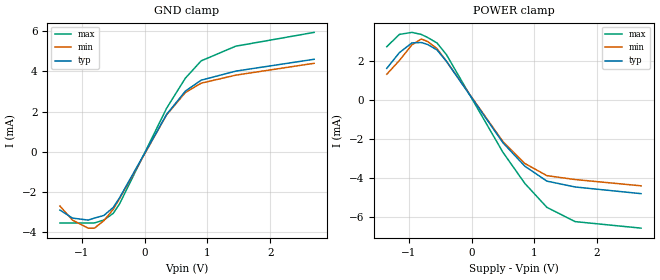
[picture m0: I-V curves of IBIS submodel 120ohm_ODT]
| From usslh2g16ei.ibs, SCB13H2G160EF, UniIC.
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| SUBMODEL 120ohm_ODT
[Submodel]   120ohm_ODT
Submodel_type  Dynamic_clamp
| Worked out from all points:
|   GND clamp passes 1 mA (typ) near -0.17 V on its own axis
|   POWER clamp passes 1 mA (typ) near -0.20 V on its own axis
[GND Clamp]
|Voltage   I(typ)   I(min)   I(max)
-1.35V    -2.9mA     -2.7mA     -3.542mA
-1.15V    -3.3mA     -3.4mA     -3.542mA
-900mV    -3.4mA     -3.8mA     -3.542mA
-800mV    -3.3mA     -3.8mA     -3.542mA
-650mV    -3.17mA    -3.43mA    -3.396mA
-500mV    -2.77mA    -2.86mA    -3.063mA
-400mV    -2.29mA    -2.33mA    -2.594mA
350mV     1.86mA     1.84mA     2.167mA
650mV     3.02mA     2.95mA     3.667mA
900mV     3.56mA     3.41mA     4.521mA
1.45V     4.01mA     3.81mA     5.25mA
2.7V      4.6mA      4.4mA      5.938mA
[POWER Clamp]
|Voltage   I(typ)   I(min)   I(max)
-1.35V    1.6mA      1.3mA      2.708mA
-1.15V    2.4mA      2mA        3.333mA
-950mV    2.9mA      2.8mA      3.438mA
-800mV    2.92mA     3.1mA      3.333mA
-700mV    2.82mA     2.97mA     3.177mA
-550mV    2.54mA     2.61mA     2.896mA
-400mV    1.96mA     1.96mA     2.302mA
500mV     -2.2mA     -2.14mA    -2.688mA
850mV     -3.4mA     -3.26mA    -4.281mA
1.2V      -4.16mA    -3.88mA    -5.5mA
1.65V     -4.46mA    -4.08mA    -6.229mA
2.7V      -4.8mA     -4.4mA     -6.562mA
